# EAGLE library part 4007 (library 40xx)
Dual COMPLIMENTARY PAIR plus INVERTER

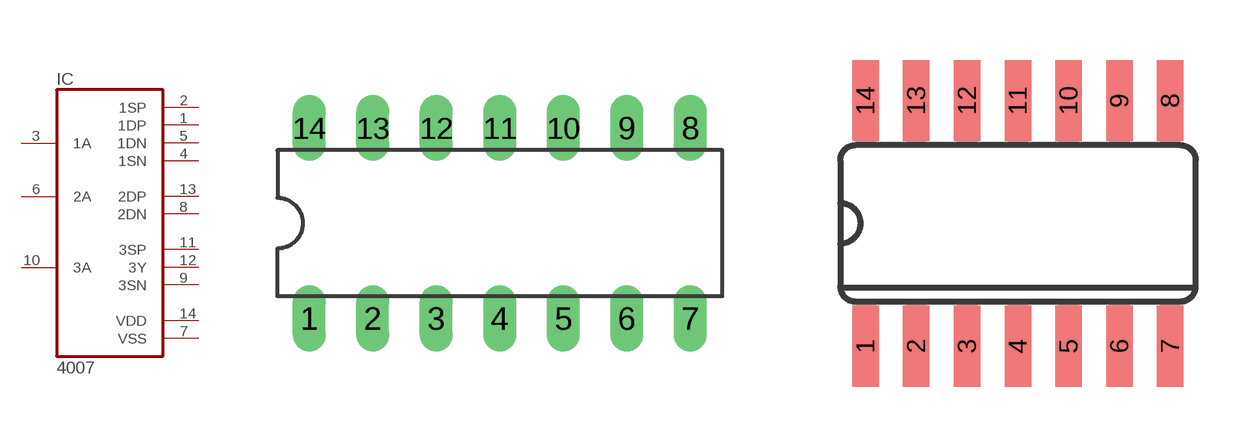
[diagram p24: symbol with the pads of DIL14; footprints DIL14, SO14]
Designator prefix IC

## 4007N  [DIL14]
1  1DP  oc
2  1SP  oc
3  1A  in
4  1SN  oc
5  1DN  oc
6  2A  in
7  VSS  in
8  2DN
9  3SN
10  3A  in
11  3SP
12  3Y
13  2DP
14  VDD  in

## 4007D  [SO14]
Pads as for DIL14

## Footprint DIL14 (pad centres in mm)
Dual In Line Package
drill 0.813 long: 1 -7.62,-3.81; 2 -5.08,-3.81; 3 -2.54,-3.81; 4 0,-3.81; 5 2.54,-3.81; 6 5.08,-3.81; 7 7.62,-3.81; 8 7.62,3.81; 9 5.08,3.81; 10 2.54,3.81; 11 0,3.81; 12 -2.54,3.81; 13 -5.08,3.81; 14 -7.62,3.81

## Footprint SO14 (pad centres in mm)
Small Outline package 150 mil
smd 0.66 x 2.032: 1 -3.81,-3.073; 2 -2.54,-3.073; 3 -1.27,-3.073; 4 0,-3.073; 5 1.27,-3.073; 6 2.54,-3.073; 7 3.81,-3.073; 8 3.81,3.073; 9 2.54,3.073; 10 1.27,3.073; 11 0,3.073; 12 -1.27,3.073; 13 -2.54,3.073; 14 -3.81,3.073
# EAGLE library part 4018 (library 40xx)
COUNTER/DIVIDER

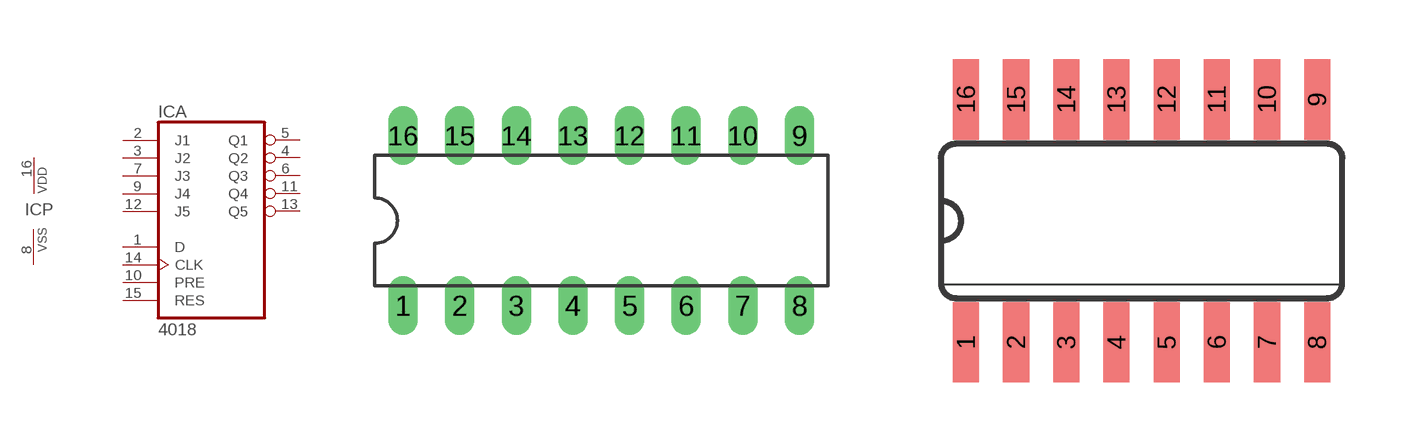
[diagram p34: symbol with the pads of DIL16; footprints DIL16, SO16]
Designator prefix IC; gates A=4018 P=PWRN

## 4018N  [DIL16]
1  A:D  in
2  A:J1  in
3  A:J2  in
4  A:Q2  out
5  A:Q1  out
6  A:Q3  out
7  A:J3  in
8  P:VSS  pwr
9  A:J4  in
10  A:PRE  in
11  A:Q4  out
12  A:J5  in
13  A:Q5  out
14  A:CLK  in
15  A:RES  in
16  P:VDD  pwr

## 4018D  [SO16]
Pads as for DIL16

## Footprint DIL16 (pad centres in mm)
Dual In Line Package
drill 0.813 long: 1 -8.89,-3.81; 2 -6.35,-3.81; 3 -3.81,-3.81; 4 -1.27,-3.81; 5 1.27,-3.81; 6 3.81,-3.81; 7 6.35,-3.81; 8 8.89,-3.81; 9 8.89,3.81; 10 6.35,3.81; 11 3.81,3.81; 12 1.27,3.81; 13 -1.27,3.81; 14 -3.81,3.81; 15 -6.35,3.81; 16 -8.89,3.81

## Footprint SO16 (pad centres in mm)
Small Outline package 150 mil
smd 0.66 x 2.032: 1 -4.445,-3.073; 2 -3.175,-3.073; 3 -1.905,-3.073; 4 -0.635,-3.073; 5 0.635,-3.073; 6 1.905,-3.073; 7 3.175,-3.073; 8 4.445,-3.073; 9 4.445,3.073; 10 3.175,3.073; 11 1.905,3.073; 12 0.635,3.073; 13 -0.635,3.073; 14 -1.905,3.073; 15 -3.175,3.073; 16 -4.445,3.073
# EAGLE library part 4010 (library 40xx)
Hex BUFFER, Non-inverting Source: www.fairchildsemi.com CD4010.pdf © 2000 Fairchild Semiconductor Corporation DS005945

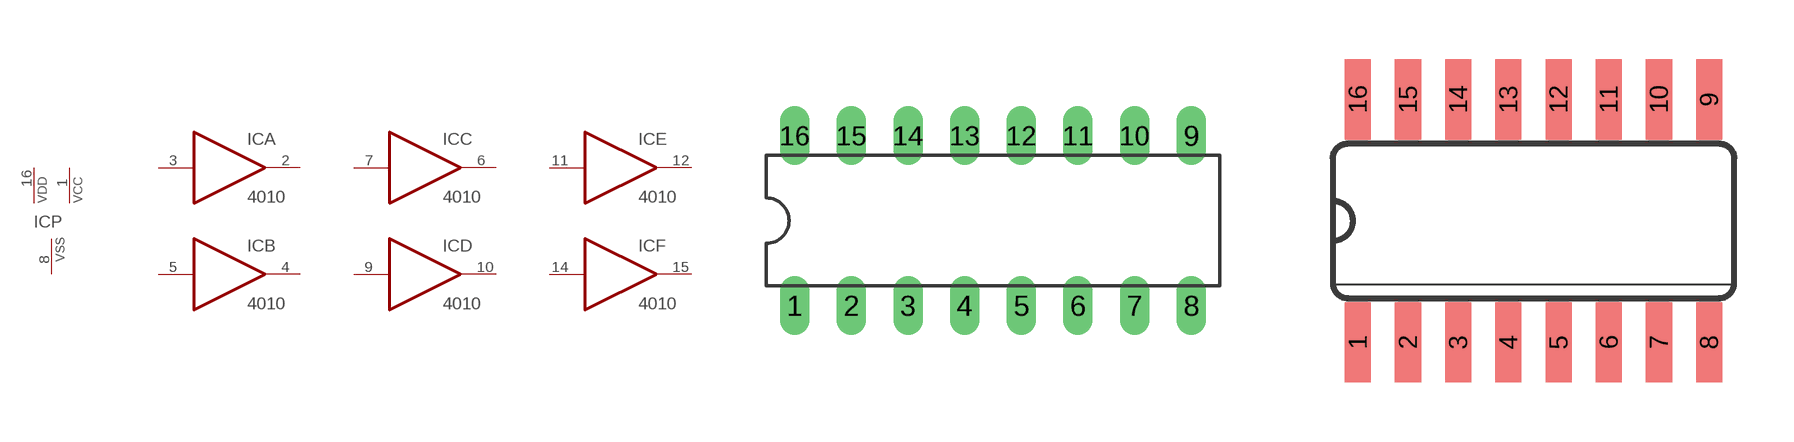
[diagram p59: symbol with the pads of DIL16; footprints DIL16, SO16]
Designator prefix IC; gates A=4010 B=4010 C=4010 D=4010 E=4010 F=4010 P=PWR3

## 4010N  [DIL16]
1  P:VCC  pwr
2  A:O  out
3  A:I  in
4  B:O  out
5  B:I  in
6  C:O  out
7  C:I  in
8  P:VSS  pwr
9  D:I  in
10  D:O  out
11  E:I  in
12  E:O  out
14  F:I  in
15  F:O  out
16  P:VDD  pwr

## 4010D  [SO16]
Pads as for DIL16

## Footprint DIL16 (pad centres in mm)
Dual In Line Package
drill 0.813 long: 1 -8.89,-3.81; 2 -6.35,-3.81; 3 -3.81,-3.81; 4 -1.27,-3.81; 5 1.27,-3.81; 6 3.81,-3.81; 7 6.35,-3.81; 8 8.89,-3.81; 9 8.89,3.81; 10 6.35,3.81; 11 3.81,3.81; 12 1.27,3.81; 13 -1.27,3.81; 14 -3.81,3.81; 15 -6.35,3.81; 16 -8.89,3.81

## Footprint SO16 (pad centres in mm)
Small Outline package 150 mil
smd 0.66 x 2.032: 1 -4.445,-3.073; 2 -3.175,-3.073; 3 -1.905,-3.073; 4 -0.635,-3.073; 5 0.635,-3.073; 6 1.905,-3.073; 7 3.175,-3.073; 8 4.445,-3.073; 9 4.445,3.073; 10 3.175,3.073; 11 1.905,3.073; 12 0.635,3.073; 13 -0.635,3.073; 14 -1.905,3.073; 15 -3.175,3.073; 16 -4.445,3.073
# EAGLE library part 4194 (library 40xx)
4-bit universal SHIFT REGISTER

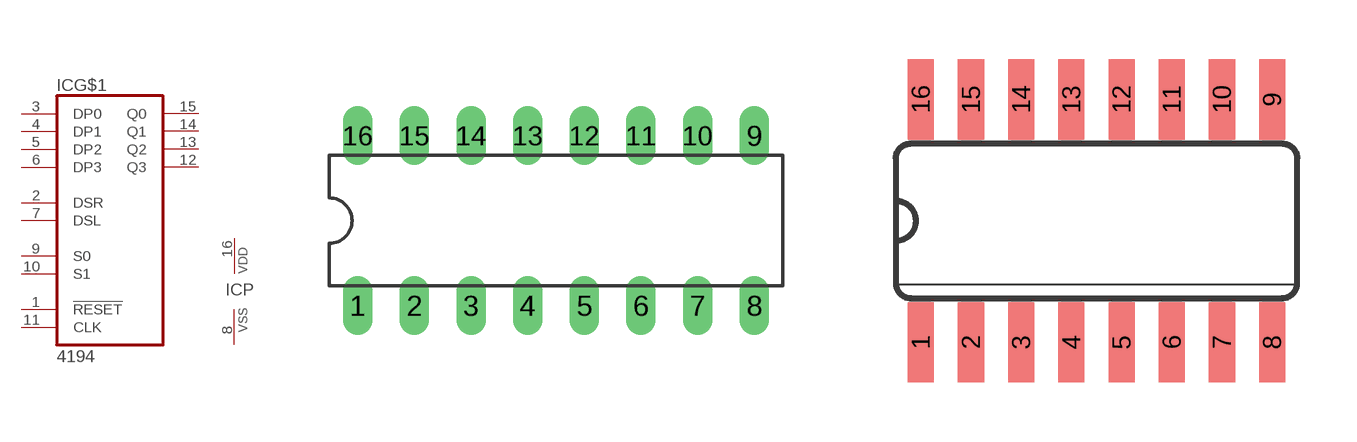
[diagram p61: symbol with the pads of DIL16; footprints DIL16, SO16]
Designator prefix IC; gates P=PWRN G$1=4194

## 4194N  [DIL16]
1  G$1:!RESET  in
2  G$1:DSR  in
3  G$1:DP0  in
4  G$1:DP1  in
5  G$1:DP2  in
6  G$1:DP3  in
7  G$1:DSL  in
8  P:VSS  pwr
9  G$1:S0  in
10  G$1:S1  in
11  G$1:CLK  in
12  G$1:Q3  out
13  G$1:Q2  out
14  G$1:Q1  out
15  G$1:Q0  out
16  P:VDD  pwr

## 4194D  [SO16]
Pads as for DIL16

## Footprint DIL16 (pad centres in mm)
Dual In Line Package
drill 0.813 long: 1 -8.89,-3.81; 2 -6.35,-3.81; 3 -3.81,-3.81; 4 -1.27,-3.81; 5 1.27,-3.81; 6 3.81,-3.81; 7 6.35,-3.81; 8 8.89,-3.81; 9 8.89,3.81; 10 6.35,3.81; 11 3.81,3.81; 12 1.27,3.81; 13 -1.27,3.81; 14 -3.81,3.81; 15 -6.35,3.81; 16 -8.89,3.81

## Footprint SO16 (pad centres in mm)
Small Outline package 150 mil
smd 0.66 x 2.032: 1 -4.445,-3.073; 2 -3.175,-3.073; 3 -1.905,-3.073; 4 -0.635,-3.073; 5 0.635,-3.073; 6 1.905,-3.073; 7 3.175,-3.073; 8 4.445,-3.073; 9 4.445,3.073; 10 3.175,3.073; 11 1.905,3.073; 12 0.635,3.073; 13 -0.635,3.073; 14 -1.905,3.073; 15 -3.175,3.073; 16 -4.445,3.073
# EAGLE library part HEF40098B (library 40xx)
Hex inverting buffer, 3-state Source: Data sheet

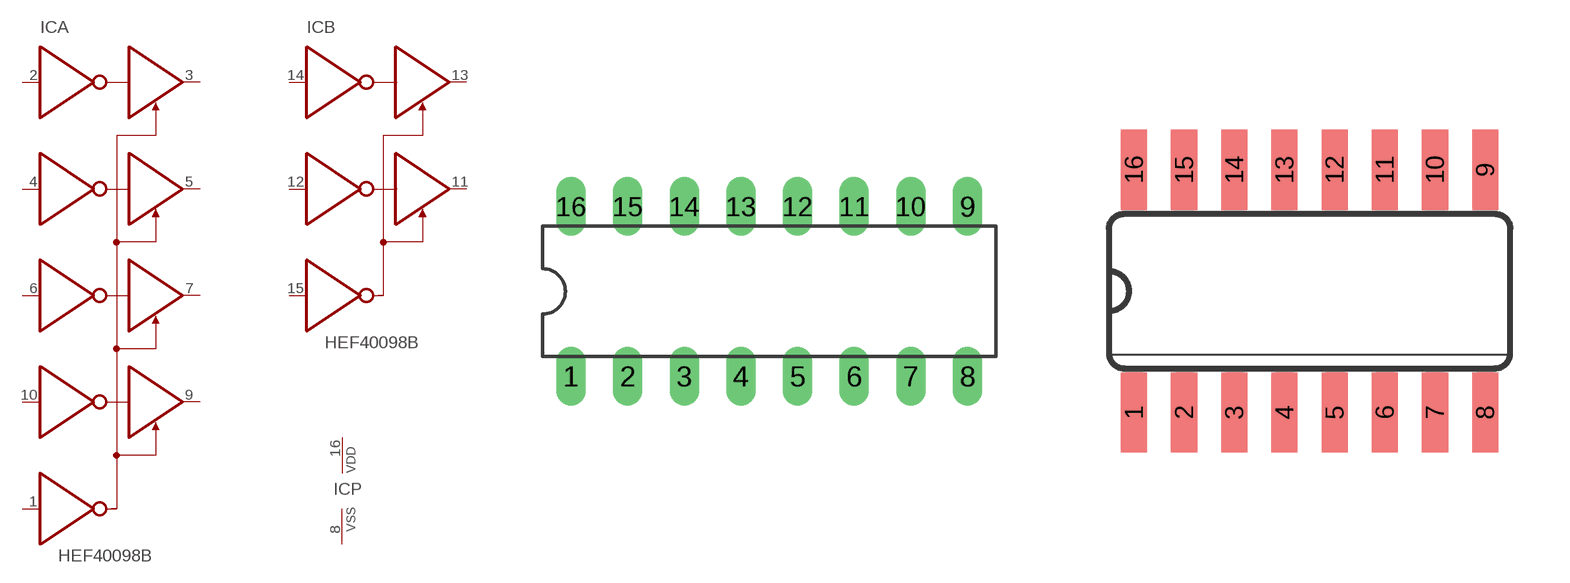
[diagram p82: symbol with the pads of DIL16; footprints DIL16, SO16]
Designator prefix IC; gates A=HEF40098A B=HEF40098B P=PWRN

## HEF40098BP  [DIL16]
1  A:1!OE  in
2  A:1A0  in
3  A:1Y0  out
4  A:1A1  in
5  A:1Y1  out
6  A:1A2  in
7  A:1Y2  out
8  P:VSS  pwr
9  A:1Y3  out
10  A:1A3  in
11  B:2Y1  out
12  B:2A1  in
13  B:2Y0  out
14  B:2A0  in
15  B:2!OE  in
16  P:VDD  pwr

## HEF40098BT  [SO16]
Pads as for DIL16

## Footprint DIL16 (pad centres in mm)
Dual In Line Package
drill 0.813 long: 1 -8.89,-3.81; 2 -6.35,-3.81; 3 -3.81,-3.81; 4 -1.27,-3.81; 5 1.27,-3.81; 6 3.81,-3.81; 7 6.35,-3.81; 8 8.89,-3.81; 9 8.89,3.81; 10 6.35,3.81; 11 3.81,3.81; 12 1.27,3.81; 13 -1.27,3.81; 14 -3.81,3.81; 15 -6.35,3.81; 16 -8.89,3.81

## Footprint SO16 (pad centres in mm)
Small Outline package 150 mil
smd 0.66 x 2.032: 1 -4.445,-3.073; 2 -3.175,-3.073; 3 -1.905,-3.073; 4 -0.635,-3.073; 5 0.635,-3.073; 6 1.905,-3.073; 7 3.175,-3.073; 8 4.445,-3.073; 9 4.445,3.073; 10 3.175,3.073; 11 1.905,3.073; 12 0.635,3.073; 13 -0.635,3.073; 14 -1.905,3.073; 15 -3.175,3.073; 16 -4.445,3.073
